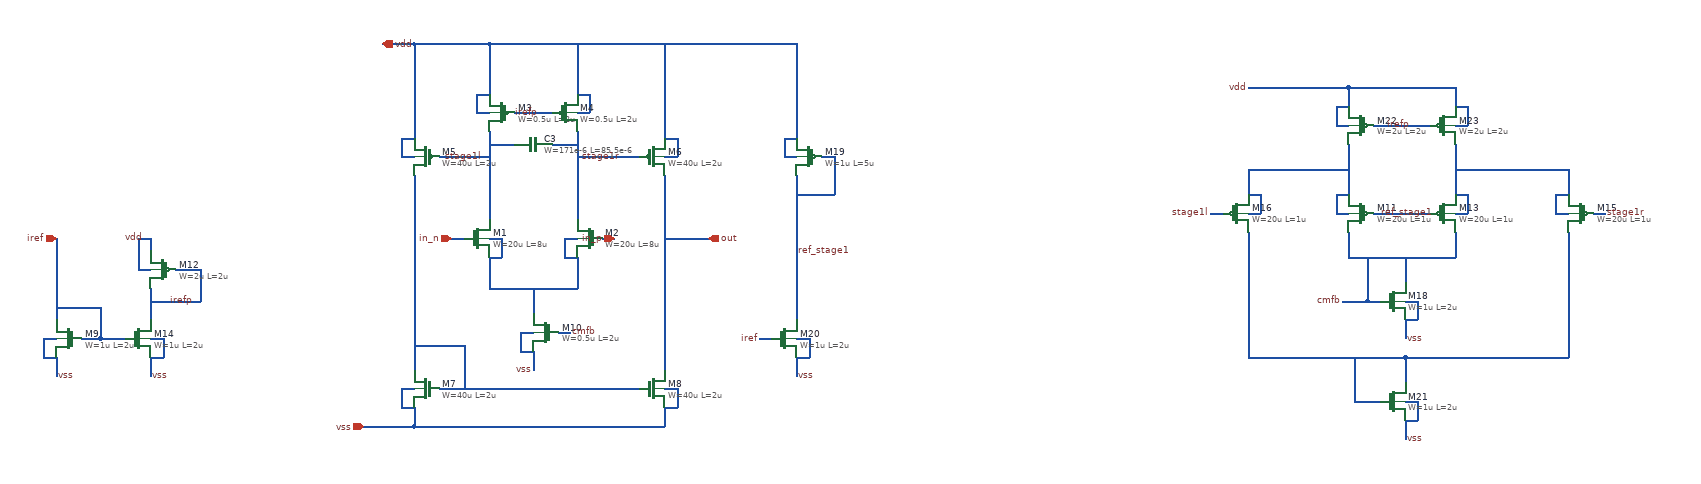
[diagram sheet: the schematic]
v {xschem version=3.4.8RC file_version=1.3}
G {}
K {}
V {}
S {}
F {}
E {}
N 600 -610 600 -560 {lab=#net1}
N 460 -560 480 -560 {lab=#net1}
N 400 -640 420 -640 {lab=in_n}
N 640 -640 660 -640 {lab=in_p}
N 460 -640 480 -640 {lab=#net1}
N 480 -640 480 -610 {lab=#net1}
N 460 -610 480 -610 {lab=#net1}
N 580 -640 600 -640 {lab=#net1}
N 580 -610 600 -610 {lab=#net1}
N 580 -640 580 -610 {lab=#net1}
N 600 -840 620 -840 {lab=vdd}
N 600 -870 620 -870 {lab=vdd}
N 440 -840 460 -840 {lab=vdd}
N 440 -870 460 -870 {lab=vdd}
N 320 -770 340 -770 {lab=vdd}
N 320 -800 320 -770 {lab=vdd}
N 320 -800 340 -800 {lab=vdd}
N 740 -770 760 -770 {lab=vdd}
N 740 -800 760 -800 {lab=vdd}
N 760 -800 760 -770 {lab=vdd}
N 320 -400 340 -400 {lab=vss}
N 320 -370 340 -370 {lab=vss}
N 320 -400 320 -370 {lab=vss}
N 740 -400 760 -400 {lab=vss}
N 760 -400 760 -370 {lab=vss}
N 740 -370 760 -370 {lab=vss}
N 380 -400 440 -400 {lab=#net2}
N 340 -340 430 -340 {lab=vss}
N 740 -370 740 -340 {lab=vss}
N 380 -770 460 -770 {lab=stage1l}
N -250 -480 -230 -480 {lab=vss}
N -250 -450 -230 -450 {lab=vss}
N -250 -480 -250 -450 {lab=vss}
N -230 -450 -230 -420 {lab=vss}
N 510 -460 530 -460 {lab=vss}
N -160 -530 -160 -480 {lab=iref}
N -230 -530 -160 -530 {lab=iref}
N -230 -640 -230 -510 {lab=iref}
N 530 -560 530 -520 {lab=#net1}
N 340 -950 340 -800 {lab=vdd}
N 440 -870 440 -840 {lab=vdd}
N 620 -870 620 -840 {lab=vdd}
N 460 -610 460 -560 {lab=#net1}
N 340 -370 340 -340 {lab=vss}
N 530 -460 530 -430 {lab=vss}
N 460 -950 460 -870 {lab=vdd}
N 340 -950 460 -950 {lab=vdd}
N 570 -490 590 -490 {lab=cmfb}
N 510 -490 510 -460 {lab=vss}
N 510 -490 530 -490 {lab=vss}
N 740 -740 740 -430 {lab=out}
N 340 -740 340 -430 {lab=#net2}
N -100 -590 -80 -590 {lab=vdd}
N -80 -450 -60 -450 {lab=vss}
N -80 -450 -80 -420 {lab=vss}
N -60 -480 -60 -450 {lab=vss}
N -80 -480 -60 -480 {lab=vss}
N -160 -480 -120 -480 {lab=iref}
N -80 -560 -80 -510 {lab=irefp}
N -80 -540 0 -540 {lab=irefp}
N 0 -590 0 -540 {lab=irefp}
N 2000 -680 2020 -680 {lab=#net3}
N 2000 -710 2020 -710 {lab=#net3}
N 1810 -680 1830 -680 {lab=#net4}
N 1810 -710 1830 -710 {lab=#net4}
N 2160 -680 2180 -680 {lab=#net3}
N 2160 -710 2160 -680 {lab=#net3}
N 2160 -710 2180 -710 {lab=#net3}
N 1670 -680 1690 -680 {lab=#net4}
N 1670 -710 1690 -710 {lab=#net4}
N 1690 -710 1690 -680 {lab=#net4}
N 1920 -510 1940 -510 {lab=vss}
N 1920 -610 1920 -570 {lab=cmfb}
N 1810 -710 1810 -680 {lab=#net4}
N 2000 -790 2000 -710 {lab=#net3}
N 2020 -710 2020 -680 {lab=#net3}
N 1920 -510 1920 -480 {lab=vss}
N 1830 -790 1830 -710 {lab=#net4}
N 1940 -540 1940 -510 {lab=vss}
N 1920 -540 1940 -540 {lab=vss}
N 930 -800 930 -770 {lab=vdd}
N 930 -770 950 -770 {lab=vdd}
N 930 -800 950 -800 {lab=vdd}
N 950 -450 970 -450 {lab=vss}
N 950 -450 950 -420 {lab=vss}
N 970 -480 970 -450 {lab=vss}
N 950 -480 970 -480 {lab=vss}
N 1920 -350 1940 -350 {lab=vss}
N 1920 -450 1920 -410 {lab=#net5}
N 1920 -350 1920 -320 {lab=vss}
N 1940 -380 1940 -350 {lab=vss}
N 1920 -380 1940 -380 {lab=vss}
N 1670 -450 1920 -450 {lab=#net5}
N 1920 -450 2180 -450 {lab=#net5}
N 1840 -380 1880 -380 {lab=#net5}
N 1840 -450 1840 -380 {lab=#net5}
N 1860 -540 1880 -540 {lab=cmfb}
N 1860 -610 1860 -540 {lab=cmfb}
N 1820 -540 1860 -540 {lab=cmfb}
N 2000 -820 2020 -820 {lab=vdd}
N 2000 -850 2020 -850 {lab=vdd}
N 1810 -820 1830 -820 {lab=vdd}
N 1810 -850 1830 -850 {lab=vdd}
N 1810 -850 1810 -820 {lab=vdd}
N 2020 -850 2020 -820 {lab=vdd}
N 1870 -820 1960 -820 {lab=irefp}
N 1830 -880 1830 -850 {lab=vdd}
N 1830 -880 1920 -880 {lab=vdd}
N 2000 -880 2000 -850 {lab=vdd}
N 1920 -880 2000 -880 {lab=vdd}
N 1870 -680 1960 -680 {lab=ref_stage1}
N 950 -740 950 -640 {lab=ref_stage1}
N 1010 -770 1010 -710 {lab=ref_stage1}
N 1830 -650 1830 -610 {lab=cmfb}
N 2000 -650 2000 -610 {lab=cmfb}
N 1830 -610 2000 -610 {lab=cmfb}
N 950 -640 950 -510 {lab=ref_stage1}
N 890 -480 910 -480 {lab=iref}
N 1670 -750 1830 -750 {lab=#net4}
N 2000 -750 2180 -750 {lab=#net3}
N 990 -770 1010 -770 {lab=ref_stage1}
N 290 -950 340 -950 {lab=vdd}
N 260 -340 340 -340 {lab=vss}
N -190 -480 -160 -480 {lab=iref}
N -40 -590 0 -590 {lab=irefp}
N -100 -640 -100 -590 {lab=vdd}
N -80 -640 -80 -620 {lab=vdd}
N -100 -640 -80 -640 {lab=vdd}
N 1670 -650 1670 -450 {lab=#net5}
N 1670 -750 1670 -710 {lab=#net4}
N 2180 -650 2180 -450 {lab=#net5}
N 2180 -750 2180 -710 {lab=#net3}
N 1670 -880 1830 -880 {lab=vdd}
N 950 -950 950 -800 {lab=vdd}
N 1610 -680 1630 -680 {lab=stage1l}
N 2220 -680 2240 -680 {lab=stage1r}
N 480 -560 570 -560 {lab=#net1}
N 570 -560 600 -560 {lab=#net1}
N 460 -950 670 -950 {lab=vdd}
N 600 -950 600 -870 {lab=vdd}
N 500 -840 560 -840 {lab=irefp}
N 460 -810 460 -670 {lab=stage1l}
N 600 -810 600 -670 {lab=stage1r}
N 950 -710 1010 -710 {lab=ref_stage1}
N 600 -770 700 -770 {lab=stage1r}
N 440 -400 700 -400 {lab=#net2}
N 430 -340 740 -340 {lab=vss}
N 340 -470 420 -470 {lab=#net2}
N 420 -470 420 -400 {lab=#net2}
N 740 -950 740 -800 {lab=vdd}
N 740 -640 810 -640 {lab=out}
N 460 -790 500 -790 {lab=stage1l}
N 560 -790 600 -790 {lab=stage1r}
N 670 -950 950 -950 {lab=vdd}
C {symbols/nfet_03v3.sym} 440 -640 0 0 {name=M1
L=8u
W=20u
nf=1
m=1
ad="'int((nf+1)/2) * W/nf * 0.18u'"
pd="'2*int((nf+1)/2) * (W/nf + 0.18u)'"
as="'int((nf+2)/2) * W/nf * 0.18u'"
ps="'2*int((nf+2)/2) * (W/nf + 0.18u)'"
nrd="'0.18u / W'" nrs="'0.18u / W'"
sa=0 sb=0 sd=0
model=nfet_03v3
spiceprefix=X
}
C {symbols/nfet_03v3.sym} 620 -640 0 1 {name=M2
L=8u
W=20u
u
nf=1
m=1
ad="'int((nf+1)/2) * W/nf * 0.18u'"
pd="'2*int((nf+1)/2) * (W/nf + 0.18u)'"
as="'int((nf+2)/2) * W/nf * 0.18u'"
ps="'2*int((nf+2)/2) * (W/nf + 0.18u)'"
nrd="'0.18u / W'" nrs="'0.18u / W'"
sa=0 sb=0 sd=0
model=nfet_03v3
spiceprefix=X
}
C {symbols/pfet_03v3.sym} 480 -840 0 1 {name=M3
L=2u
W=0.5u
nf=1
m=1
ad="'int((nf+1)/2) * W/nf * 0.18u'"
pd="'2*int((nf+1)/2) * (W/nf + 0.18u)'"
as="'int((nf+2)/2) * W/nf * 0.18u'"
ps="'2*int((nf+2)/2) * (W/nf + 0.18u)'"
nrd="'0.18u / W'" nrs="'0.18u / W'"
sa=0 sb=0 sd=0
model=pfet_03v3
spiceprefix=X
}
C {symbols/pfet_03v3.sym} 580 -840 0 0 {name=M4
L=2u
W=0.5u
nf=1
m=1
ad="'int((nf+1)/2) * W/nf * 0.18u'"
pd="'2*int((nf+1)/2) * (W/nf + 0.18u)'"
as="'int((nf+2)/2) * W/nf * 0.18u'"
ps="'2*int((nf+2)/2) * (W/nf + 0.18u)'"
nrd="'0.18u / W'" nrs="'0.18u / W'"
sa=0 sb=0 sd=0
model=pfet_03v3
spiceprefix=X
}
C {opin.sym} 810 -640 0 0 {name=p5 lab=out}
C {ipin.sym} 400 -640 0 0 {name=p4 lab=in_n}
C {ipin.sym} 660 -640 2 0 {name=p1 lab=in_p}
C {iopin.sym} 290 -950 0 1 {name=p3 lab=vdd
}
C {iopin.sym} 260 -340 2 0 {name=p6 lab=vss}
C {symbols/pfet_03v3.sym} 360 -770 0 1 {name=M5
L=2u
W=40u
nf=1
m=1
ad="'int((nf+1)/2) * W/nf * 0.18u'"
pd="'2*int((nf+1)/2) * (W/nf + 0.18u)'"
as="'int((nf+2)/2) * W/nf * 0.18u'"
ps="'2*int((nf+2)/2) * (W/nf + 0.18u)'"
nrd="'0.18u / W'" nrs="'0.18u / W'"
sa=0 sb=0 sd=0
model=pfet_03v3
spiceprefix=X
}
C {symbols/pfet_03v3.sym} 720 -770 0 0 {name=M6
L=2u
W=40u
nf=1
m=1
ad="'int((nf+1)/2) * W/nf * 0.18u'"
pd="'2*int((nf+1)/2) * (W/nf + 0.18u)'"
as="'int((nf+2)/2) * W/nf * 0.18u'"
ps="'2*int((nf+2)/2) * (W/nf + 0.18u)'"
nrd="'0.18u / W'" nrs="'0.18u / W'"
sa=0 sb=0 sd=0
model=pfet_03v3
spiceprefix=X
}
C {symbols/nfet_03v3.sym} 360 -400 0 1 {name=M7
L=2u
W=40u
nf=1
m=1
ad="'int((nf+1)/2) * W/nf * 0.18u'"
pd="'2*int((nf+1)/2) * (W/nf + 0.18u)'"
as="'int((nf+2)/2) * W/nf * 0.18u'"
ps="'2*int((nf+2)/2) * (W/nf + 0.18u)'"
nrd="'0.18u / W'" nrs="'0.18u / W'"
sa=0 sb=0 sd=0
model=nfet_03v3
spiceprefix=X
}
C {symbols/nfet_03v3.sym} 720 -400 0 0 {name=M8
L=2u
W=40u
nf=1
m=1
ad="'int((nf+1)/2) * W/nf * 0.18u'"
pd="'2*int((nf+1)/2) * (W/nf + 0.18u)'"
as="'int((nf+2)/2) * W/nf * 0.18u'"
ps="'2*int((nf+2)/2) * (W/nf + 0.18u)'"
nrd="'0.18u / W'" nrs="'0.18u / W'"
sa=0 sb=0 sd=0
model=nfet_03v3
spiceprefix=X
}
C {symbols/nfet_03v3.sym} -210 -480 0 1 {name=M9
L=2u
W=1u
u
nf=1
m=1
ad="'int((nf+1)/2) * W/nf * 0.18u'"
pd="'2*int((nf+1)/2) * (W/nf + 0.18u)'"
as="'int((nf+2)/2) * W/nf * 0.18u'"
ps="'2*int((nf+2)/2) * (W/nf + 0.18u)'"
nrd="'0.18u / W'" nrs="'0.18u / W'"
sa=0 sb=0 sd=0
model=nfet_03v3
spiceprefix=X
}
C {lab_wire.sym} -230 -420 2 0 {name=p2 sig_type=std_logic lab=vss
}
C {symbols/nfet_03v3.sym} 550 -490 0 1 {name=M10
L=2u
W=0.5u
nf=1
m=1
ad="'int((nf+1)/2) * W/nf * 0.18u'"
pd="'2*int((nf+1)/2) * (W/nf + 0.18u)'"
as="'int((nf+2)/2) * W/nf * 0.18u'"
ps="'2*int((nf+2)/2) * (W/nf + 0.18u)'"
nrd="'0.18u / W'" nrs="'0.18u / W'"
sa=0 sb=0 sd=0
model=nfet_03v3
spiceprefix=X
}
C {lab_wire.sym} 530 -430 2 1 {name=p7 sig_type=std_logic lab=vss
}
C {iopin.sym} -230 -640 3 0 {name=p8 lab=iref

}
C {symbols/pfet_03v3.sym} -60 -590 0 1 {name=M12
L=2u
W=2u
nf=1
m=1
ad="'int((nf+1)/2) * W/nf * 0.18u'"
pd="'2*int((nf+1)/2) * (W/nf + 0.18u)'"
as="'int((nf+2)/2) * W/nf * 0.18u'"
ps="'2*int((nf+2)/2) * (W/nf + 0.18u)'"
nrd="'0.18u / W'" nrs="'0.18u / W'"
sa=0 sb=0 sd=0
model=pfet_03v3
spiceprefix=X
}
C {symbols/nfet_03v3.sym} -100 -480 0 0 {name=M14
L=2u
W=1u
nf=1
m=1
ad="'int((nf+1)/2) * W/nf * 0.18u'"
pd="'2*int((nf+1)/2) * (W/nf + 0.18u)'"
as="'int((nf+2)/2) * W/nf * 0.18u'"
ps="'2*int((nf+2)/2) * (W/nf + 0.18u)'"
nrd="'0.18u / W'" nrs="'0.18u / W'"
sa=0 sb=0 sd=0
model=nfet_03v3
spiceprefix=X
}
C {lab_wire.sym} -80 -420 2 0 {name=p9 sig_type=std_logic lab=vss
}
C {title.sym} 160 0 0 0 {name=l1 author="Tobias Huber"}
C {symbols/pfet_03v3.sym} 1850 -680 0 1 {name=M11
L=1u
W=20u
nf=1
m=1
ad="'int((nf+1)/2) * W/nf * 0.18u'"
pd="'2*int((nf+1)/2) * (W/nf + 0.18u)'"
as="'int((nf+2)/2) * W/nf * 0.18u'"
ps="'2*int((nf+2)/2) * (W/nf + 0.18u)'"
nrd="'0.18u / W'" nrs="'0.18u / W'"
sa=0 sb=0 sd=0
model=pfet_03v3
spiceprefix=X
}
C {symbols/pfet_03v3.sym} 1980 -680 0 0 {name=M13
L=1u
W=20u
nf=1
m=1
ad="'int((nf+1)/2) * W/nf * 0.18u'"
pd="'2*int((nf+1)/2) * (W/nf + 0.18u)'"
as="'int((nf+2)/2) * W/nf * 0.18u'"
ps="'2*int((nf+2)/2) * (W/nf + 0.18u)'"
nrd="'0.18u / W'" nrs="'0.18u / W'"
sa=0 sb=0 sd=0
model=pfet_03v3
spiceprefix=X
}
C {symbols/pfet_03v3.sym} 2200 -680 0 1 {name=M15
L=1u
W=20u
nf=1
m=1
ad="'int((nf+1)/2) * W/nf * 0.18u'"
pd="'2*int((nf+1)/2) * (W/nf + 0.18u)'"
as="'int((nf+2)/2) * W/nf * 0.18u'"
ps="'2*int((nf+2)/2) * (W/nf + 0.18u)'"
nrd="'0.18u / W'" nrs="'0.18u / W'"
sa=0 sb=0 sd=0
model=pfet_03v3
spiceprefix=X
}
C {symbols/pfet_03v3.sym} 1650 -680 0 0 {name=M16
L=1u
W=20u
nf=1
m=1
ad="'int((nf+1)/2) * W/nf * 0.18u'"
pd="'2*int((nf+1)/2) * (W/nf + 0.18u)'"
as="'int((nf+2)/2) * W/nf * 0.18u'"
ps="'2*int((nf+2)/2) * (W/nf + 0.18u)'"
nrd="'0.18u / W'" nrs="'0.18u / W'"
sa=0 sb=0 sd=0
model=pfet_03v3
spiceprefix=X
}
C {symbols/nfet_03v3.sym} 1900 -540 0 0 {name=M18
L=2u
W=1u
nf=1
m=1
ad="'int((nf+1)/2) * W/nf * 0.18u'"
pd="'2*int((nf+1)/2) * (W/nf + 0.18u)'"
as="'int((nf+2)/2) * W/nf * 0.18u'"
ps="'2*int((nf+2)/2) * (W/nf + 0.18u)'"
nrd="'0.18u / W'" nrs="'0.18u / W'"
sa=0 sb=0 sd=0
model=nfet_03v3
spiceprefix=X
}
C {lab_wire.sym} 1920 -480 2 0 {name=p18 sig_type=std_logic lab=vss
}
C {symbols/pfet_03v3.sym} 970 -770 0 1 {name=M19
L=5u
W=1u
nf=1
m=1
ad="'int((nf+1)/2) * W/nf * 0.18u'"
pd="'2*int((nf+1)/2) * (W/nf + 0.18u)'"
as="'int((nf+2)/2) * W/nf * 0.18u'"
ps="'2*int((nf+2)/2) * (W/nf + 0.18u)'"
nrd="'0.18u / W'" nrs="'0.18u / W'"
sa=0 sb=0 sd=0
model=pfet_03v3
spiceprefix=X
}
C {symbols/nfet_03v3.sym} 930 -480 0 0 {name=M20
L=2u
W=1u
nf=1
m=1
ad="'int((nf+1)/2) * W/nf * 0.18u'"
pd="'2*int((nf+1)/2) * (W/nf + 0.18u)'"
as="'int((nf+2)/2) * W/nf * 0.18u'"
ps="'2*int((nf+2)/2) * (W/nf + 0.18u)'"
nrd="'0.18u / W'" nrs="'0.18u / W'"
sa=0 sb=0 sd=0
model=nfet_03v3
spiceprefix=X
}
C {lab_wire.sym} 950 -420 2 0 {name=p20 sig_type=std_logic lab=vss
}
C {symbols/nfet_03v3.sym} 1900 -380 0 0 {name=M21
L=2u
W=1u
nf=1
m=1
ad="'int((nf+1)/2) * W/nf * 0.18u'"
pd="'2*int((nf+1)/2) * (W/nf + 0.18u)'"
as="'int((nf+2)/2) * W/nf * 0.18u'"
ps="'2*int((nf+2)/2) * (W/nf + 0.18u)'"
nrd="'0.18u / W'" nrs="'0.18u / W'"
sa=0 sb=0 sd=0
model=nfet_03v3
spiceprefix=X
}
C {symbols/pfet_03v3.sym} 1850 -820 0 1 {name=M22
L=2u
W=2u
nf=1
m=1
ad="'int((nf+1)/2) * W/nf * 0.18u'"
pd="'2*int((nf+1)/2) * (W/nf + 0.18u)'"
as="'int((nf+2)/2) * W/nf * 0.18u'"
ps="'2*int((nf+2)/2) * (W/nf + 0.18u)'"
nrd="'0.18u / W'" nrs="'0.18u / W'"
sa=0 sb=0 sd=0
model=pfet_03v3
spiceprefix=X
}
C {symbols/pfet_03v3.sym} 1980 -820 0 0 {name=M23
L=2u
W=2u
nf=1
m=1
ad="'int((nf+1)/2) * W/nf * 0.18u'"
pd="'2*int((nf+1)/2) * (W/nf + 0.18u)'"
as="'int((nf+2)/2) * W/nf * 0.18u'"
ps="'2*int((nf+2)/2) * (W/nf + 0.18u)'"
nrd="'0.18u / W'" nrs="'0.18u / W'"
sa=0 sb=0 sd=0
model=pfet_03v3
spiceprefix=X
}
C {lab_wire.sym} -90 -640 0 0 {name=p10 sig_type=std_logic lab=vdd
}
C {lab_wire.sym} -10 -540 0 0 {name=p11 sig_type=std_logic lab=irefp
}
C {lab_wire.sym} 540 -840 0 0 {name=p13 sig_type=std_logic lab=irefp
}
C {lab_wire.sym} 590 -490 0 1 {name=p14 sig_type=std_logic lab=cmfb
}
C {lab_wire.sym} 1820 -540 0 0 {name=p12 sig_type=std_logic lab=cmfb
}
C {lab_wire.sym} 1670 -880 0 0 {name=p15 sig_type=std_logic lab=vdd
}
C {lab_wire.sym} 1920 -320 2 0 {name=p16 sig_type=std_logic lab=vss
}
C {lab_wire.sym} 1930 -820 0 0 {name=p17 sig_type=std_logic lab=irefp
}
C {lab_wire.sym} 450 -770 0 0 {name=p19 sig_type=std_logic lab=stage1l
}
C {lab_wire.sym} 670 -770 0 0 {name=p21 sig_type=std_logic lab=stage1r
}
C {lab_wire.sym} 950 -620 2 0 {name=p22 sig_type=std_logic lab=ref_stage1
}
C {lab_wire.sym} 1880 -680 2 0 {name=p23 sig_type=std_logic lab=ref_stage1
}
C {lab_wire.sym} 2240 -680 2 0 {name=p24 sig_type=std_logic lab=stage1r
}
C {lab_wire.sym} 1610 -680 2 1 {name=p25 sig_type=std_logic lab=stage1l
}
C {lab_wire.sym} 890 -480 2 1 {name=p26 sig_type=std_logic lab=iref
}
C {symbols/cap_mim_2f0fF.sym} 530 -790 1 0 {name=C3
W=171e-6
L=85.5e-6
model=cap_mim_2f0fF
spiceprefix=X
m=1}
